VERSION 5.7 ;
  NOWIREEXTENSIONATPIN ON ;
  DIVIDERCHAR "/" ;
  BUSBITCHARS "[]" ;
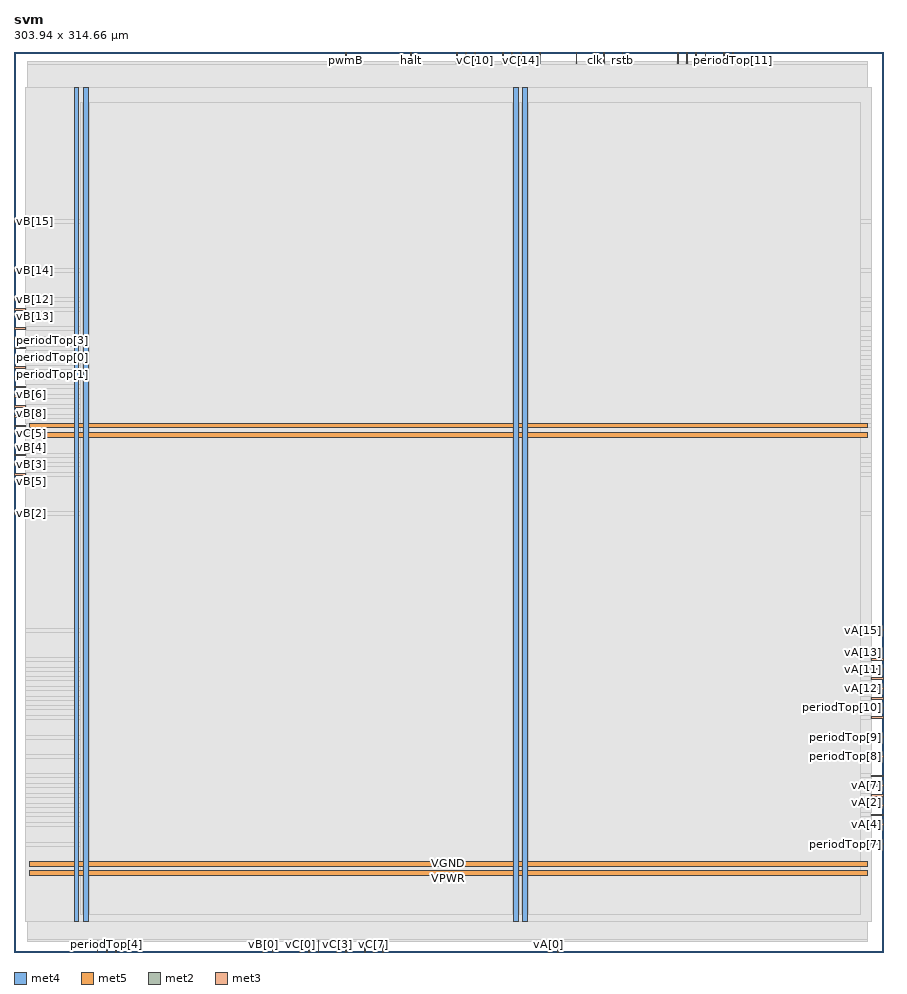
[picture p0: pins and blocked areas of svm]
MACRO svm
  CLASS BLOCK ;
  FOREIGN svm ;
  ORIGIN 0.000 0.000 ;
  SIZE 303.940 BY 314.660 ;
  PIN VGND
    DIRECTION INOUT ;
    USE GROUND ;
    PORT
      LAYER met4 ;
        RECT 24.340 10.640 25.940 302.160 ;
    END
    PORT
      LAYER met4 ;
        RECT 177.940 10.640 179.540 302.160 ;
    END
    PORT
      LAYER met5 ;
        RECT 5.280 30.030 298.320 31.630 ;
    END
    PORT
      LAYER met5 ;
        RECT 5.280 183.210 298.320 184.810 ;
    END
  END VGND
  PIN VPWR
    DIRECTION INOUT ;
    USE POWER ;
    PORT
      LAYER met4 ;
        RECT 21.040 10.640 22.640 302.160 ;
    END
    PORT
      LAYER met4 ;
        RECT 174.640 10.640 176.240 302.160 ;
    END
    PORT
      LAYER met5 ;
        RECT 5.280 26.730 298.320 28.330 ;
    END
    PORT
      LAYER met5 ;
        RECT 5.280 179.910 298.320 181.510 ;
    END
  END VPWR
  PIN clk
    DIRECTION INPUT ;
    USE SIGNAL ;
    ANTENNAGATEAREA 0.852000 ;
    PORT
      LAYER met2 ;
        RECT 202.950 310.660 203.230 314.660 ;
    END
  END clk
  PIN halt
    DIRECTION OUTPUT ;
    USE SIGNAL ;
    ANTENNADIFFAREA 0.795200 ;
    PORT
      LAYER met2 ;
        RECT 138.550 310.660 138.830 314.660 ;
    END
  END halt
  PIN periodTop[0]
    DIRECTION INPUT ;
    USE SIGNAL ;
    ANTENNAGATEAREA 0.196500 ;
    PORT
      LAYER met3 ;
        RECT 0.000 207.440 4.000 208.040 ;
    END
  END periodTop[0]
  PIN periodTop[10]
    DIRECTION INPUT ;
    USE SIGNAL ;
    ANTENNAGATEAREA 0.495000 ;
    PORT
      LAYER met3 ;
        RECT 299.940 85.040 303.940 85.640 ;
    END
  END periodTop[10]
  PIN periodTop[11]
    DIRECTION INPUT ;
    USE SIGNAL ;
    ANTENNAGATEAREA 0.196500 ;
    PORT
      LAYER met2 ;
        RECT 251.250 310.660 251.530 314.660 ;
    END
  END periodTop[11]
  PIN periodTop[12]
    DIRECTION INPUT ;
    USE SIGNAL ;
    ANTENNAGATEAREA 0.213000 ;
    PORT
      LAYER met2 ;
        RECT 241.590 310.660 241.870 314.660 ;
    END
  END periodTop[12]
  PIN periodTop[13]
    DIRECTION INPUT ;
    USE SIGNAL ;
    ANTENNAGATEAREA 0.213000 ;
    PORT
      LAYER met2 ;
        RECT 238.370 310.660 238.650 314.660 ;
    END
  END periodTop[13]
  PIN periodTop[14]
    DIRECTION INPUT ;
    USE SIGNAL ;
    ANTENNAGATEAREA 0.196500 ;
    PORT
      LAYER met2 ;
        RECT 235.150 310.660 235.430 314.660 ;
    END
  END periodTop[14]
  PIN periodTop[15]
    DIRECTION INPUT ;
    USE SIGNAL ;
    ANTENNAGATEAREA 0.213000 ;
    PORT
      LAYER met2 ;
        RECT 231.930 310.660 232.210 314.660 ;
    END
  END periodTop[15]
  PIN periodTop[1]
    DIRECTION INPUT ;
    USE SIGNAL ;
    ANTENNAGATEAREA 0.196500 ;
    PORT
      LAYER met3 ;
        RECT 0.000 204.040 4.000 204.640 ;
    END
  END periodTop[1]
  PIN periodTop[2]
    DIRECTION INPUT ;
    USE SIGNAL ;
    ANTENNAGATEAREA 0.213000 ;
    PORT
      LAYER met3 ;
        RECT 0.000 200.640 4.000 201.240 ;
    END
  END periodTop[2]
  PIN periodTop[3]
    DIRECTION INPUT ;
    USE SIGNAL ;
    ANTENNAGATEAREA 0.213000 ;
    PORT
      LAYER met3 ;
        RECT 0.000 210.840 4.000 211.440 ;
    END
  END periodTop[3]
  PIN periodTop[4]
    DIRECTION INPUT ;
    USE SIGNAL ;
    ANTENNAGATEAREA 0.196500 ;
    PORT
      LAYER met2 ;
        RECT 32.290 0.000 32.570 4.000 ;
    END
  END periodTop[4]
  PIN periodTop[5]
    DIRECTION INPUT ;
    USE SIGNAL ;
    ANTENNAGATEAREA 0.213000 ;
    PORT
      LAYER met2 ;
        RECT 29.070 0.000 29.350 4.000 ;
    END
  END periodTop[5]
  PIN periodTop[6]
    DIRECTION INPUT ;
    USE SIGNAL ;
    ANTENNAGATEAREA 0.196500 ;
    PORT
      LAYER met2 ;
        RECT 35.510 0.000 35.790 4.000 ;
    END
  END periodTop[6]
  PIN periodTop[7]
    DIRECTION INPUT ;
    USE SIGNAL ;
    ANTENNAGATEAREA 0.213000 ;
    PORT
      LAYER met3 ;
        RECT 299.940 37.440 303.940 38.040 ;
    END
  END periodTop[7]
  PIN periodTop[8]
    DIRECTION INPUT ;
    USE SIGNAL ;
    ANTENNAGATEAREA 0.159000 ;
    PORT
      LAYER met3 ;
        RECT 299.940 68.040 303.940 68.640 ;
    END
  END periodTop[8]
  PIN periodTop[9]
    DIRECTION INPUT ;
    USE SIGNAL ;
    ANTENNAGATEAREA 0.213000 ;
    PORT
      LAYER met3 ;
        RECT 299.940 74.840 303.940 75.440 ;
    END
  END periodTop[9]
  PIN pwmA
    DIRECTION OUTPUT ;
    USE SIGNAL ;
    ANTENNADIFFAREA 0.891000 ;
    PORT
      LAYER met2 ;
        RECT 206.170 310.660 206.450 314.660 ;
    END
  END pwmA
  PIN pwmB
    DIRECTION OUTPUT ;
    USE SIGNAL ;
    ANTENNADIFFAREA 1.336500 ;
    PORT
      LAYER met2 ;
        RECT 116.010 310.660 116.290 314.660 ;
    END
  END pwmB
  PIN pwmC
    DIRECTION OUTPUT ;
    USE SIGNAL ;
    ANTENNADIFFAREA 0.795200 ;
    PORT
      LAYER met2 ;
        RECT 196.510 310.660 196.790 314.660 ;
    END
  END pwmC
  PIN rstb
    DIRECTION INPUT ;
    USE SIGNAL ;
    ANTENNAGATEAREA 0.196500 ;
    PORT
      LAYER met2 ;
        RECT 212.610 310.660 212.890 314.660 ;
    END
  END rstb
  PIN vA[0]
    DIRECTION INPUT ;
    USE SIGNAL ;
    ANTENNAGATEAREA 0.213000 ;
    PORT
      LAYER met2 ;
        RECT 186.850 0.000 187.130 4.000 ;
    END
  END vA[0]
  PIN vA[10]
    DIRECTION INPUT ;
    USE SIGNAL ;
    ANTENNAGATEAREA 0.196500 ;
    PORT
      LAYER met3 ;
        RECT 299.940 81.640 303.940 82.240 ;
    END
  END vA[10]
  PIN vA[11]
    DIRECTION INPUT ;
    USE SIGNAL ;
    ANTENNAGATEAREA 0.213000 ;
    PORT
      LAYER met3 ;
        RECT 299.940 98.640 303.940 99.240 ;
    END
  END vA[11]
  PIN vA[12]
    DIRECTION INPUT ;
    USE SIGNAL ;
    ANTENNAGATEAREA 0.213000 ;
    PORT
      LAYER met3 ;
        RECT 299.940 91.840 303.940 92.440 ;
    END
  END vA[12]
  PIN vA[13]
    DIRECTION INPUT ;
    USE SIGNAL ;
    ANTENNAGATEAREA 0.213000 ;
    PORT
      LAYER met3 ;
        RECT 299.940 102.040 303.940 102.640 ;
    END
  END vA[13]
  PIN vA[14]
    DIRECTION INPUT ;
    USE SIGNAL ;
    ANTENNAGATEAREA 0.213000 ;
    PORT
      LAYER met2 ;
        RECT 248.030 310.660 248.310 314.660 ;
    END
  END vA[14]
  PIN vA[15]
    DIRECTION INPUT ;
    USE SIGNAL ;
    ANTENNAGATEAREA 0.196500 ;
    PORT
      LAYER met3 ;
        RECT 299.940 112.240 303.940 112.840 ;
    END
  END vA[15]
  PIN vA[1]
    DIRECTION INPUT ;
    USE SIGNAL ;
    ANTENNAGATEAREA 0.196500 ;
    PORT
      LAYER met2 ;
        RECT 190.070 0.000 190.350 4.000 ;
    END
  END vA[1]
  PIN vA[2]
    DIRECTION INPUT ;
    USE SIGNAL ;
    ANTENNAGATEAREA 0.159000 ;
    PORT
      LAYER met3 ;
        RECT 299.940 54.440 303.940 55.040 ;
    END
  END vA[2]
  PIN vA[3]
    DIRECTION INPUT ;
    USE SIGNAL ;
    ANTENNAGATEAREA 0.213000 ;
    PORT
      LAYER met3 ;
        RECT 299.940 51.040 303.940 51.640 ;
    END
  END vA[3]
  PIN vA[4]
    DIRECTION INPUT ;
    USE SIGNAL ;
    ANTENNAGATEAREA 0.196500 ;
    PORT
      LAYER met3 ;
        RECT 299.940 44.240 303.940 44.840 ;
    END
  END vA[4]
  PIN vA[5]
    DIRECTION INPUT ;
    USE SIGNAL ;
    ANTENNAGATEAREA 0.213000 ;
    PORT
      LAYER met3 ;
        RECT 299.940 95.240 303.940 95.840 ;
    END
  END vA[5]
  PIN vA[6]
    DIRECTION INPUT ;
    USE SIGNAL ;
    ANTENNAGATEAREA 0.196500 ;
    PORT
      LAYER met3 ;
        RECT 299.940 47.640 303.940 48.240 ;
    END
  END vA[6]
  PIN vA[7]
    DIRECTION INPUT ;
    USE SIGNAL ;
    ANTENNAGATEAREA 0.213000 ;
    PORT
      LAYER met3 ;
        RECT 299.940 57.840 303.940 58.440 ;
    END
  END vA[7]
  PIN vA[8]
    DIRECTION INPUT ;
    USE SIGNAL ;
    ANTENNAGATEAREA 0.213000 ;
    PORT
      LAYER met3 ;
        RECT 299.940 61.240 303.940 61.840 ;
    END
  END vA[8]
  PIN vA[9]
    DIRECTION INPUT ;
    USE SIGNAL ;
    ANTENNAGATEAREA 0.213000 ;
    PORT
      LAYER met3 ;
        RECT 299.940 88.440 303.940 89.040 ;
    END
  END vA[9]
  PIN vB[0]
    DIRECTION INPUT ;
    USE SIGNAL ;
    ANTENNAGATEAREA 0.196500 ;
    PORT
      LAYER met2 ;
        RECT 87.030 0.000 87.310 4.000 ;
    END
  END vB[0]
  PIN vB[10]
    DIRECTION INPUT ;
    USE SIGNAL ;
    ANTENNAGATEAREA 0.196500 ;
    PORT
      LAYER met3 ;
        RECT 0.000 214.240 4.000 214.840 ;
    END
  END vB[10]
  PIN vB[11]
    DIRECTION INPUT ;
    USE SIGNAL ;
    ANTENNAGATEAREA 0.196500 ;
    PORT
      LAYER met3 ;
        RECT 0.000 217.640 4.000 218.240 ;
    END
  END vB[11]
  PIN vB[12]
    DIRECTION INPUT ;
    USE SIGNAL ;
    ANTENNAGATEAREA 0.196500 ;
    PORT
      LAYER met3 ;
        RECT 0.000 227.840 4.000 228.440 ;
    END
  END vB[12]
  PIN vB[13]
    DIRECTION INPUT ;
    USE SIGNAL ;
    ANTENNAGATEAREA 0.196500 ;
    PORT
      LAYER met3 ;
        RECT 0.000 224.440 4.000 225.040 ;
    END
  END vB[13]
  PIN vB[14]
    DIRECTION INPUT ;
    USE SIGNAL ;
    ANTENNAGATEAREA 0.247500 ;
    PORT
      LAYER met3 ;
        RECT 0.000 238.040 4.000 238.640 ;
    END
  END vB[14]
  PIN vB[15]
    DIRECTION INPUT ;
    USE SIGNAL ;
    ANTENNAGATEAREA 0.213000 ;
    PORT
      LAYER met3 ;
        RECT 0.000 255.040 4.000 255.640 ;
    END
  END vB[15]
  PIN vB[1]
    DIRECTION INPUT ;
    USE SIGNAL ;
    ANTENNAGATEAREA 0.196500 ;
    PORT
      LAYER met2 ;
        RECT 90.250 0.000 90.530 4.000 ;
    END
  END vB[1]
  PIN vB[2]
    DIRECTION INPUT ;
    USE SIGNAL ;
    ANTENNAGATEAREA 0.213000 ;
    PORT
      LAYER met3 ;
        RECT 0.000 153.040 4.000 153.640 ;
    END
  END vB[2]
  PIN vB[3]
    DIRECTION INPUT ;
    USE SIGNAL ;
    ANTENNAGATEAREA 0.196500 ;
    PORT
      LAYER met3 ;
        RECT 0.000 170.040 4.000 170.640 ;
    END
  END vB[3]
  PIN vB[4]
    DIRECTION INPUT ;
    USE SIGNAL ;
    ANTENNAGATEAREA 0.196500 ;
    PORT
      LAYER met3 ;
        RECT 0.000 173.440 4.000 174.040 ;
    END
  END vB[4]
  PIN vB[5]
    DIRECTION INPUT ;
    USE SIGNAL ;
    ANTENNAGATEAREA 0.213000 ;
    PORT
      LAYER met3 ;
        RECT 0.000 166.640 4.000 167.240 ;
    END
  END vB[5]
  PIN vB[6]
    DIRECTION INPUT ;
    USE SIGNAL ;
    ANTENNAGATEAREA 0.213000 ;
    PORT
      LAYER met3 ;
        RECT 0.000 197.240 4.000 197.840 ;
    END
  END vB[6]
  PIN vB[7]
    DIRECTION INPUT ;
    USE SIGNAL ;
    ANTENNAGATEAREA 0.196500 ;
    PORT
      LAYER met3 ;
        RECT 0.000 193.840 4.000 194.440 ;
    END
  END vB[7]
  PIN vB[8]
    DIRECTION INPUT ;
    USE SIGNAL ;
    ANTENNAGATEAREA 0.126000 ;
    PORT
      LAYER met3 ;
        RECT 0.000 190.440 4.000 191.040 ;
    END
  END vB[8]
  PIN vB[9]
    DIRECTION INPUT ;
    USE SIGNAL ;
    ANTENNAGATEAREA 0.196500 ;
    PORT
      LAYER met3 ;
        RECT 0.000 187.040 4.000 187.640 ;
    END
  END vB[9]
  PIN vC[0]
    DIRECTION INPUT ;
    USE SIGNAL ;
    ANTENNAGATEAREA 0.213000 ;
    PORT
      LAYER met2 ;
        RECT 99.910 0.000 100.190 4.000 ;
    END
  END vC[0]
  PIN vC[10]
    DIRECTION INPUT ;
    USE SIGNAL ;
    ANTENNAGATEAREA 0.196500 ;
    PORT
      LAYER met2 ;
        RECT 161.090 310.660 161.370 314.660 ;
    END
  END vC[10]
  PIN vC[11]
    DIRECTION INPUT ;
    USE SIGNAL ;
    ANTENNAGATEAREA 0.196500 ;
    PORT
      LAYER met2 ;
        RECT 157.870 310.660 158.150 314.660 ;
    END
  END vC[11]
  PIN vC[12]
    DIRECTION INPUT ;
    USE SIGNAL ;
    ANTENNAGATEAREA 0.196500 ;
    PORT
      LAYER met2 ;
        RECT 173.970 310.660 174.250 314.660 ;
    END
  END vC[12]
  PIN vC[13]
    DIRECTION INPUT ;
    USE SIGNAL ;
    ANTENNAGATEAREA 0.196500 ;
    PORT
      LAYER met2 ;
        RECT 170.750 310.660 171.030 314.660 ;
    END
  END vC[13]
  PIN vC[14]
    DIRECTION INPUT ;
    USE SIGNAL ;
    ANTENNAGATEAREA 0.213000 ;
    PORT
      LAYER met2 ;
        RECT 177.190 310.660 177.470 314.660 ;
    END
  END vC[14]
  PIN vC[15]
    DIRECTION INPUT ;
    USE SIGNAL ;
    ANTENNAGATEAREA 0.196500 ;
    PORT
      LAYER met2 ;
        RECT 183.630 310.660 183.910 314.660 ;
    END
  END vC[15]
  PIN vC[1]
    DIRECTION INPUT ;
    USE SIGNAL ;
    ANTENNAGATEAREA 0.196500 ;
    PORT
      LAYER met2 ;
        RECT 103.130 0.000 103.410 4.000 ;
    END
  END vC[1]
  PIN vC[2]
    DIRECTION INPUT ;
    USE SIGNAL ;
    ANTENNAGATEAREA 0.213000 ;
    PORT
      LAYER met2 ;
        RECT 106.350 0.000 106.630 4.000 ;
    END
  END vC[2]
  PIN vC[3]
    DIRECTION INPUT ;
    USE SIGNAL ;
    ANTENNAGATEAREA 0.196500 ;
    PORT
      LAYER met2 ;
        RECT 112.790 0.000 113.070 4.000 ;
    END
  END vC[3]
  PIN vC[4]
    DIRECTION INPUT ;
    USE SIGNAL ;
    ANTENNAGATEAREA 0.196500 ;
    PORT
      LAYER met2 ;
        RECT 116.010 0.000 116.290 4.000 ;
    END
  END vC[4]
  PIN vC[5]
    DIRECTION INPUT ;
    USE SIGNAL ;
    ANTENNAGATEAREA 0.213000 ;
    PORT
      LAYER met3 ;
        RECT 0.000 183.640 4.000 184.240 ;
    END
  END vC[5]
  PIN vC[6]
    DIRECTION INPUT ;
    USE SIGNAL ;
    ANTENNAGATEAREA 0.196500 ;
    PORT
      LAYER met2 ;
        RECT 122.450 0.000 122.730 4.000 ;
    END
  END vC[6]
  PIN vC[7]
    DIRECTION INPUT ;
    USE SIGNAL ;
    ANTENNAGATEAREA 0.159000 ;
    PORT
      LAYER met2 ;
        RECT 125.670 0.000 125.950 4.000 ;
    END
  END vC[7]
  PIN vC[8]
    DIRECTION INPUT ;
    USE SIGNAL ;
    ANTENNAGATEAREA 0.159000 ;
    PORT
      LAYER met2 ;
        RECT 128.890 0.000 129.170 4.000 ;
    END
  END vC[8]
  PIN vC[9]
    DIRECTION INPUT ;
    USE SIGNAL ;
    ANTENNAGATEAREA 0.196500 ;
    PORT
      LAYER met2 ;
        RECT 154.650 310.660 154.930 314.660 ;
    END
  END vC[9]
  OBS
      LAYER li1 ;
        RECT 5.520 10.795 298.080 302.005 ;
      LAYER met1 ;
        RECT 4.670 10.640 298.470 302.160 ;
      LAYER met2 ;
        RECT 4.690 310.380 115.730 311.170 ;
        RECT 116.570 310.380 138.270 311.170 ;
        RECT 139.110 310.380 154.370 311.170 ;
        RECT 155.210 310.380 157.590 311.170 ;
        RECT 158.430 310.380 160.810 311.170 ;
        RECT 161.650 310.380 170.470 311.170 ;
        RECT 171.310 310.380 173.690 311.170 ;
        RECT 174.530 310.380 176.910 311.170 ;
        RECT 177.750 310.380 183.350 311.170 ;
        RECT 184.190 310.380 196.230 311.170 ;
        RECT 197.070 310.380 202.670 311.170 ;
        RECT 203.510 310.380 205.890 311.170 ;
        RECT 206.730 310.380 212.330 311.170 ;
        RECT 213.170 310.380 231.650 311.170 ;
        RECT 232.490 310.380 234.870 311.170 ;
        RECT 235.710 310.380 238.090 311.170 ;
        RECT 238.930 310.380 241.310 311.170 ;
        RECT 242.150 310.380 247.750 311.170 ;
        RECT 248.590 310.380 250.970 311.170 ;
        RECT 251.810 310.380 298.450 311.170 ;
        RECT 4.690 4.280 298.450 310.380 ;
        RECT 4.690 3.670 28.790 4.280 ;
        RECT 29.630 3.670 32.010 4.280 ;
        RECT 32.850 3.670 35.230 4.280 ;
        RECT 36.070 3.670 86.750 4.280 ;
        RECT 87.590 3.670 89.970 4.280 ;
        RECT 90.810 3.670 99.630 4.280 ;
        RECT 100.470 3.670 102.850 4.280 ;
        RECT 103.690 3.670 106.070 4.280 ;
        RECT 106.910 3.670 112.510 4.280 ;
        RECT 113.350 3.670 115.730 4.280 ;
        RECT 116.570 3.670 122.170 4.280 ;
        RECT 123.010 3.670 125.390 4.280 ;
        RECT 126.230 3.670 128.610 4.280 ;
        RECT 129.450 3.670 186.570 4.280 ;
        RECT 187.410 3.670 189.790 4.280 ;
        RECT 190.630 3.670 298.450 4.280 ;
      LAYER met3 ;
        RECT 4.000 256.040 299.940 302.085 ;
        RECT 4.400 254.640 299.940 256.040 ;
        RECT 4.000 239.040 299.940 254.640 ;
        RECT 4.400 237.640 299.940 239.040 ;
        RECT 4.000 228.840 299.940 237.640 ;
        RECT 4.400 227.440 299.940 228.840 ;
        RECT 4.000 225.440 299.940 227.440 ;
        RECT 4.400 224.040 299.940 225.440 ;
        RECT 4.000 218.640 299.940 224.040 ;
        RECT 4.400 217.240 299.940 218.640 ;
        RECT 4.000 215.240 299.940 217.240 ;
        RECT 4.400 213.840 299.940 215.240 ;
        RECT 4.000 211.840 299.940 213.840 ;
        RECT 4.400 210.440 299.940 211.840 ;
        RECT 4.000 208.440 299.940 210.440 ;
        RECT 4.400 207.040 299.940 208.440 ;
        RECT 4.000 205.040 299.940 207.040 ;
        RECT 4.400 203.640 299.940 205.040 ;
        RECT 4.000 201.640 299.940 203.640 ;
        RECT 4.400 200.240 299.940 201.640 ;
        RECT 4.000 198.240 299.940 200.240 ;
        RECT 4.400 196.840 299.940 198.240 ;
        RECT 4.000 194.840 299.940 196.840 ;
        RECT 4.400 193.440 299.940 194.840 ;
        RECT 4.000 191.440 299.940 193.440 ;
        RECT 4.400 190.040 299.940 191.440 ;
        RECT 4.000 188.040 299.940 190.040 ;
        RECT 4.400 186.640 299.940 188.040 ;
        RECT 4.000 184.640 299.940 186.640 ;
        RECT 4.400 183.240 299.940 184.640 ;
        RECT 4.000 174.440 299.940 183.240 ;
        RECT 4.400 173.040 299.940 174.440 ;
        RECT 4.000 171.040 299.940 173.040 ;
        RECT 4.400 169.640 299.940 171.040 ;
        RECT 4.000 167.640 299.940 169.640 ;
        RECT 4.400 166.240 299.940 167.640 ;
        RECT 4.000 154.040 299.940 166.240 ;
        RECT 4.400 152.640 299.940 154.040 ;
        RECT 4.000 113.240 299.940 152.640 ;
        RECT 4.000 111.840 299.540 113.240 ;
        RECT 4.000 103.040 299.940 111.840 ;
        RECT 4.000 101.640 299.540 103.040 ;
        RECT 4.000 99.640 299.940 101.640 ;
        RECT 4.000 98.240 299.540 99.640 ;
        RECT 4.000 96.240 299.940 98.240 ;
        RECT 4.000 94.840 299.540 96.240 ;
        RECT 4.000 92.840 299.940 94.840 ;
        RECT 4.000 91.440 299.540 92.840 ;
        RECT 4.000 89.440 299.940 91.440 ;
        RECT 4.000 88.040 299.540 89.440 ;
        RECT 4.000 86.040 299.940 88.040 ;
        RECT 4.000 84.640 299.540 86.040 ;
        RECT 4.000 82.640 299.940 84.640 ;
        RECT 4.000 81.240 299.540 82.640 ;
        RECT 4.000 75.840 299.940 81.240 ;
        RECT 4.000 74.440 299.540 75.840 ;
        RECT 4.000 69.040 299.940 74.440 ;
        RECT 4.000 67.640 299.540 69.040 ;
        RECT 4.000 62.240 299.940 67.640 ;
        RECT 4.000 60.840 299.540 62.240 ;
        RECT 4.000 58.840 299.940 60.840 ;
        RECT 4.000 57.440 299.540 58.840 ;
        RECT 4.000 55.440 299.940 57.440 ;
        RECT 4.000 54.040 299.540 55.440 ;
        RECT 4.000 52.040 299.940 54.040 ;
        RECT 4.000 50.640 299.540 52.040 ;
        RECT 4.000 48.640 299.940 50.640 ;
        RECT 4.000 47.240 299.540 48.640 ;
        RECT 4.000 45.240 299.940 47.240 ;
        RECT 4.000 43.840 299.540 45.240 ;
        RECT 4.000 38.440 299.940 43.840 ;
        RECT 4.000 37.040 299.540 38.440 ;
        RECT 4.000 10.715 299.940 37.040 ;
      LAYER met4 ;
        RECT 23.295 13.095 23.940 296.985 ;
        RECT 26.340 13.095 174.240 296.985 ;
        RECT 176.640 13.095 177.540 296.985 ;
        RECT 179.940 13.095 295.945 296.985 ;
  END
END svm
END LIBRARY

